VERSION 5.7 ;
  NOWIREEXTENSIONATPIN ON ;
  DIVIDERCHAR "/" ;
  BUSBITCHARS "[]" ;
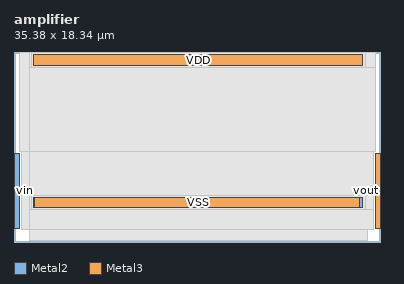
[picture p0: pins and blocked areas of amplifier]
MACRO amplifier
  CLASS BLOCK ;
  FOREIGN amplifier ;
  ORIGIN 1.100 3.060 ;
  SIZE 35.380 BY 18.340 ;
  PIN vin
    ANTENNAGATEAREA 140.000000 ;
    PORT
      LAYER Metal2 ;
        RECT -1.100 -1.730 -0.600 5.480 ;
    END
  END vin
  PIN VDD
    USE POWER ;
    PORT
      LAYER Metal2 ;
        RECT 0.805 14.020 32.575 15.040 ;
      LAYER Metal3 ;
        RECT 0.805 14.020 32.575 15.040 ;
    END
  END VDD
  PIN VSS
    USE GROUND ;
    PORT
      LAYER Metal2 ;
        RECT 0.805 0.240 0.900 1.260 ;
        RECT 32.280 0.240 32.575 1.260 ;
      LAYER Metal3 ;
        RECT 0.805 0.240 32.575 1.260 ;
    END
  END VSS
  PIN vout
    ANTENNADIFFAREA 26.599998 ;
    PORT
      LAYER Metal3 ;
        RECT 33.780 -1.730 34.280 5.480 ;
    END
  END vout
  OBS
      LAYER GatPoly ;
        RECT 0.350 -2.930 33.030 13.780 ;
      LAYER Metal1 ;
        RECT 0.350 -2.930 33.030 15.280 ;
      LAYER Metal2 ;
        RECT -0.600 5.690 33.030 15.280 ;
        RECT -0.390 -1.830 33.030 5.690 ;
      LAYER Metal3 ;
        RECT 0.350 15.250 33.780 15.280 ;
        RECT 0.350 13.810 0.595 15.250 ;
        RECT 32.785 13.810 33.780 15.250 ;
        RECT 0.350 5.690 33.780 13.810 ;
        RECT 0.350 1.470 33.570 5.690 ;
        RECT 0.350 0.030 0.595 1.470 ;
        RECT 32.785 0.030 33.570 1.470 ;
        RECT 0.350 -1.830 33.570 0.030 ;
  END
END amplifier
END LIBRARY

